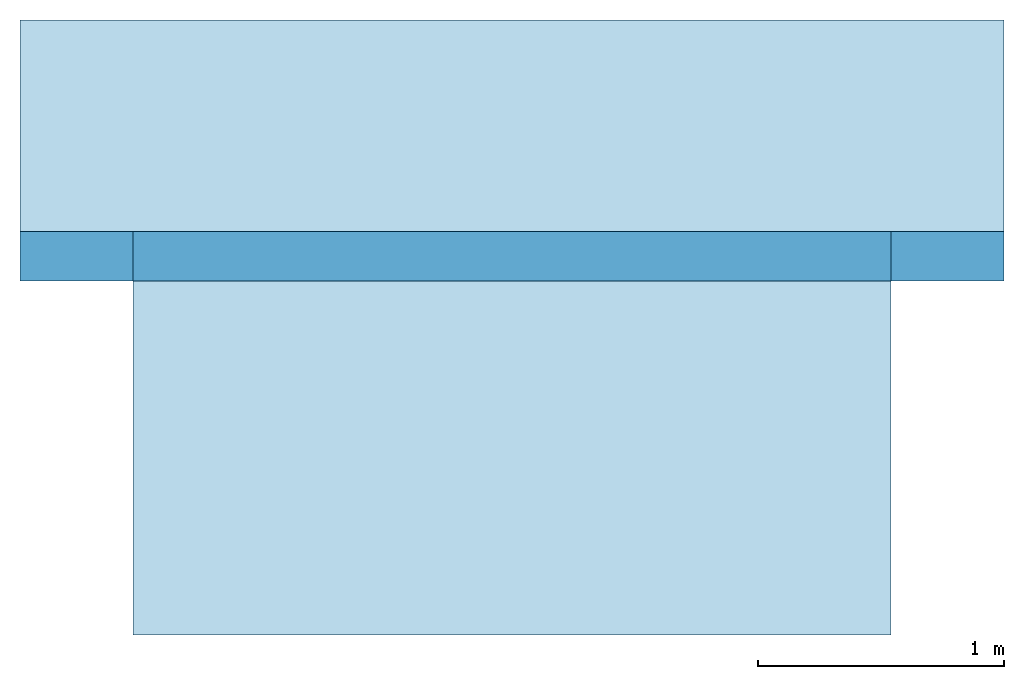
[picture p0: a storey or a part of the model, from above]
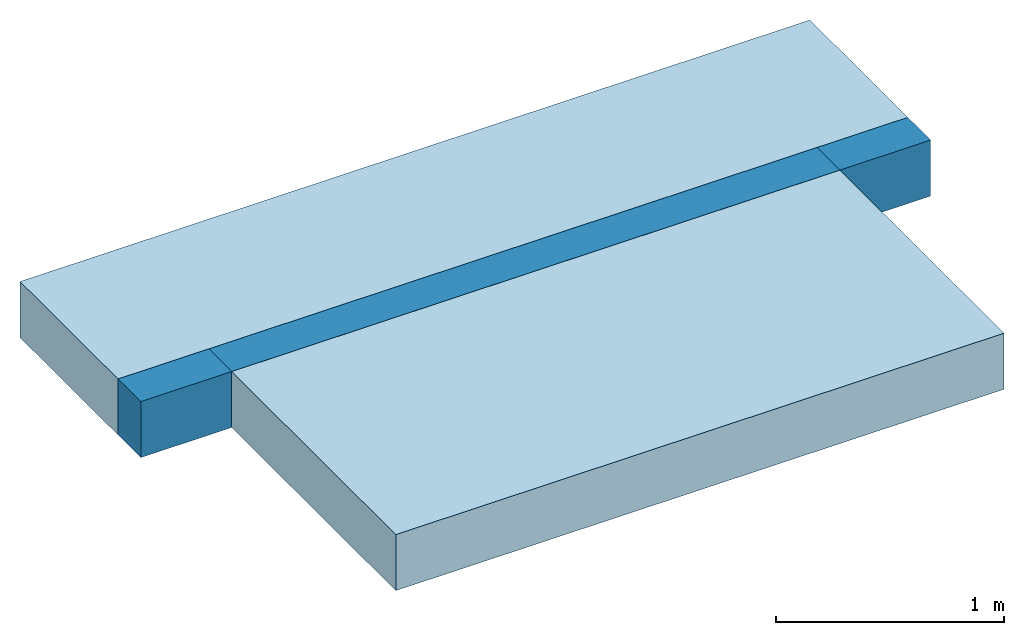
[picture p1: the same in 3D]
Properties of the parts of a building model (IFC4)

# File
Description: no view
File name: ÖBV_OEBV_Richtlinie_Thermische Trennelemente.ifc
Time: 2024-03-13T09:55:29
Author: Oesterreichische Bautechnik Vereinigung
Organization: OEBV
Written by: ODA SDAI 24.5
Authorization: OEBV

# IfcSite, Liegenschaft
RefLatitude: 48, 8, 10, 320000; RefLongitude: 11, 41, 19, 320000

# IfcBuildingStorey (2)
In: Gebäude
Elevation: 0 m
Name
Geschoss 01
Geschoss 02

# IfcBeam
In: Geschoss 01
Material: Mineralwolledämmung
AllplanAttributes - Allright_Bauteil_ID: 0029Unz0000004388

# IfcOpeningElement: Opening, Türöffnung
In: Geschoss 02
AllplanAttributes - Object Layer Attributes #1, Allright_Bauteil_ID: 0079Tür0000000008; Object Layer Attributes #2, Allright_Bauteil_ID: 0079Tür0000000006

# IfcSlab (2)
In: Geschoss 01
PredefinedType: FLOOR
Name | Allright_Bauteil_ID
 | 0029De 0000002663
 | 0029De 0000002669

# IfcWall (3)
Name | In | Material | Allright_Bauteil_ID | Object Layer Attributes #1, Allright_Bauteil_ID
 | Geschoss 01 | layer 0.2 m | 0029HWa0000004057 | 0029Wa 0000004058
 | Geschoss 01 | layer 0.2 m | 0029HWa0000004063 | 0029Wa 0000004064
WA_01 | Geschoss 02 | C20/25 0.25 m, layer 0.2 m | 0079HWa0000000002 | 0079Wa 0000000021 | AllplanAttributes - Object Layer Attributes #2, Allright_Bauteil_ID: 0079Wa 0000000017
